VERSION 5.7 ;
  NOWIREEXTENSIONATPIN ON ;
  DIVIDERCHAR "/" ;
  BUSBITCHARS "[]" ;
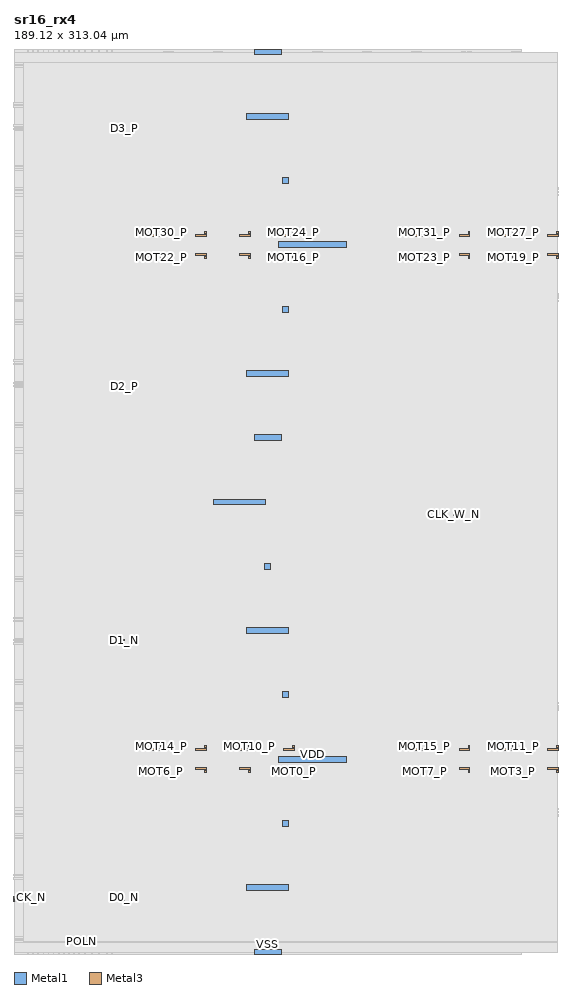
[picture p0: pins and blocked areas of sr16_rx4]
MACRO sr16_rx4
  CLASS BLOCK ;
  FOREIGN sr16_rx4 ;
  ORIGIN 0.000 0.000 ;
  SIZE 189.120 BY 313.040 ;
  PIN VSS
    DIRECTION INOUT ;
    USE GROUND ;
    USE GROUND ;
    PORT
      LAYER Metal1 ;
        RECT 83.570 -1.000 92.870 1.000 ;
    END
    PORT
      LAYER Metal1 ;
        RECT 93.560 43.720 95.560 45.720 ;
    END
    PORT
      LAYER Metal1 ;
        RECT 93.560 88.440 95.560 90.440 ;
    END
    PORT
      LAYER Metal1 ;
        RECT 87.280 133.160 89.280 135.160 ;
    END
    PORT
      LAYER Metal1 ;
        RECT 83.570 177.880 92.870 179.880 ;
    END
    PORT
      LAYER Metal1 ;
        RECT 93.560 222.600 95.560 224.600 ;
    END
    PORT
      LAYER Metal1 ;
        RECT 93.560 267.320 95.560 269.320 ;
    END
    PORT
      LAYER Metal1 ;
        RECT 83.570 312.040 92.870 314.040 ;
    END
  END VSS
  PIN VDD
    DIRECTION INOUT ;
    USE POWER ;
    USE POWER ;
    PORT
      LAYER Metal1 ;
        RECT 80.820 21.360 95.400 23.360 ;
    END
    PORT
      LAYER Metal1 ;
        RECT 91.940 66.080 115.740 68.080 ;
    END
    PORT
      LAYER Metal1 ;
        RECT 80.820 110.800 95.400 112.800 ;
    END
    PORT
      LAYER Metal1 ;
        RECT 69.450 155.520 87.440 157.520 ;
    END
    PORT
      LAYER Metal1 ;
        RECT 80.820 200.240 95.400 202.240 ;
    END
    PORT
      LAYER Metal1 ;
        RECT 91.940 244.960 115.740 246.960 ;
    END
    PORT
      LAYER Metal1 ;
        RECT 80.820 289.680 95.400 291.680 ;
    END
  END VDD
  PIN CK_N
    DIRECTION INPUT ;
    USE SIGNAL ;
    ANTENNAGATEAREA 6.480000 ;
    PORT
      LAYER Metal3 ;
        RECT -0.150 18.760 0.150 19.360 ;
    END
  END CK_N
  PIN CK_P
    DIRECTION INPUT ;
    USE SIGNAL ;
    ANTENNAGATEAREA 6.480000 ;
    PORT
      LAYER Metal3 ;
        RECT -0.150 17.660 0.150 18.260 ;
    END
  END CK_P
  PIN D0_N
    DIRECTION INPUT ;
    USE SIGNAL ;
    ANTENNAGATEAREA 1.778400 ;
    PORT
      LAYER Metal3 ;
        RECT 38.170 18.760 38.470 19.360 ;
    END
  END D0_N
  PIN D0_P
    DIRECTION INPUT ;
    USE SIGNAL ;
    ANTENNAGATEAREA 1.778400 ;
    PORT
      LAYER Metal3 ;
        RECT 38.170 17.660 38.470 18.260 ;
    END
  END D0_P
  PIN D1_N
    DIRECTION INPUT ;
    USE SIGNAL ;
    ANTENNAGATEAREA 1.778400 ;
    PORT
      LAYER Metal3 ;
        RECT 38.170 108.200 38.470 108.800 ;
    END
  END D1_N
  PIN D1_P
    DIRECTION INPUT ;
    USE SIGNAL ;
    ANTENNAGATEAREA 1.778400 ;
    PORT
      LAYER Metal3 ;
        RECT 38.170 107.100 38.470 107.700 ;
    END
  END D1_P
  PIN D2_N
    DIRECTION INPUT ;
    USE SIGNAL ;
    ANTENNAGATEAREA 1.778400 ;
    PORT
      LAYER Metal3 ;
        RECT 38.170 197.640 38.470 198.240 ;
    END
  END D2_N
  PIN D2_P
    DIRECTION INPUT ;
    USE SIGNAL ;
    ANTENNAGATEAREA 1.778400 ;
    PORT
      LAYER Metal3 ;
        RECT 38.170 196.540 38.470 197.140 ;
    END
  END D2_P
  PIN D3_N
    DIRECTION INPUT ;
    USE SIGNAL ;
    ANTENNAGATEAREA 1.778400 ;
    PORT
      LAYER Metal3 ;
        RECT 38.170 287.080 38.470 287.680 ;
    END
  END D3_N
  PIN D3_P
    DIRECTION INPUT ;
    USE SIGNAL ;
    ANTENNAGATEAREA 1.778400 ;
    PORT
      LAYER Metal3 ;
        RECT 38.170 285.980 38.470 286.580 ;
    END
  END D3_P
  PIN POLN
    DIRECTION INPUT ;
    USE SIGNAL ;
    ANTENNAGATEAREA 474.759979 ;
    PORT
      LAYER Metal3 ;
        RECT 23.370 3.580 23.670 3.880 ;
    END
  END POLN
  PIN MOT0_N
    DIRECTION OUTPUT ;
    USE SIGNAL ;
    ANTENNAGATEAREA 0.693600 ;
    ANTENNADIFFAREA 1.979400 ;
    PORT
      LAYER Metal3 ;
        RECT 93.845 63.480 97.590 64.080 ;
    END
  END MOT0_N
  PIN MOT0_P
    DIRECTION OUTPUT ;
    USE SIGNAL ;
    ANTENNAGATEAREA 0.693600 ;
    ANTENNADIFFAREA 1.979400 ;
    PORT
      LAYER Metal3 ;
        RECT 97.015 62.380 97.590 62.980 ;
    END
  END MOT0_P
  PIN MOT1_N
    DIRECTION OUTPUT ;
    USE SIGNAL ;
    ANTENNAGATEAREA 0.693600 ;
    ANTENNADIFFAREA 1.979400 ;
    PORT
      LAYER Metal3 ;
        RECT 185.525 63.480 189.270 64.080 ;
    END
  END MOT1_N
  PIN MOT1_P
    DIRECTION OUTPUT ;
    USE SIGNAL ;
    ANTENNAGATEAREA 0.693600 ;
    ANTENNADIFFAREA 1.979400 ;
    PORT
      LAYER Metal3 ;
        RECT 188.695 62.380 189.270 62.980 ;
    END
  END MOT1_P
  PIN MOT2_N
    DIRECTION OUTPUT ;
    USE SIGNAL ;
    ANTENNAGATEAREA 0.693600 ;
    ANTENNADIFFAREA 1.979400 ;
    PORT
      LAYER Metal3 ;
        RECT 78.485 63.480 82.230 64.080 ;
    END
  END MOT2_N
  PIN MOT2_P
    DIRECTION OUTPUT ;
    USE SIGNAL ;
    ANTENNAGATEAREA 0.693600 ;
    ANTENNADIFFAREA 1.979400 ;
    PORT
      LAYER Metal3 ;
        RECT 81.655 62.380 82.230 62.980 ;
    END
  END MOT2_P
  PIN MOT3_N
    DIRECTION OUTPUT ;
    USE SIGNAL ;
    ANTENNAGATEAREA 0.693600 ;
    ANTENNADIFFAREA 1.979400 ;
    PORT
      LAYER Metal3 ;
        RECT 170.165 63.480 173.910 64.080 ;
    END
  END MOT3_N
  PIN MOT3_P
    DIRECTION OUTPUT ;
    USE SIGNAL ;
    ANTENNAGATEAREA 0.693600 ;
    ANTENNADIFFAREA 1.979400 ;
    PORT
      LAYER Metal3 ;
        RECT 173.335 62.380 173.910 62.980 ;
    END
  END MOT3_P
  PIN MOT4_N
    DIRECTION OUTPUT ;
    USE SIGNAL ;
    ANTENNAGATEAREA 0.693600 ;
    ANTENNADIFFAREA 1.979400 ;
    PORT
      LAYER Metal3 ;
        RECT 63.125 63.480 66.870 64.080 ;
    END
  END MOT4_N
  PIN MOT4_P
    DIRECTION OUTPUT ;
    USE SIGNAL ;
    ANTENNAGATEAREA 0.693600 ;
    ANTENNADIFFAREA 1.979400 ;
    PORT
      LAYER Metal3 ;
        RECT 66.295 62.380 66.870 62.980 ;
    END
  END MOT4_P
  PIN MOT5_N
    DIRECTION OUTPUT ;
    USE SIGNAL ;
    ANTENNAGATEAREA 0.693600 ;
    ANTENNADIFFAREA 1.979400 ;
    PORT
      LAYER Metal3 ;
        RECT 154.805 63.480 158.550 64.080 ;
    END
  END MOT5_N
  PIN MOT5_P
    DIRECTION OUTPUT ;
    USE SIGNAL ;
    ANTENNAGATEAREA 0.693600 ;
    ANTENNADIFFAREA 1.979400 ;
    PORT
      LAYER Metal3 ;
        RECT 157.975 62.380 158.550 62.980 ;
    END
  END MOT5_P
  PIN MOT6_N
    DIRECTION OUTPUT ;
    USE SIGNAL ;
    ANTENNAGATEAREA 0.693600 ;
    ANTENNADIFFAREA 1.979400 ;
    PORT
      LAYER Metal3 ;
        RECT 47.765 63.480 51.510 64.080 ;
    END
  END MOT6_N
  PIN MOT6_P
    DIRECTION OUTPUT ;
    USE SIGNAL ;
    ANTENNAGATEAREA 0.693600 ;
    ANTENNADIFFAREA 1.979400 ;
    PORT
      LAYER Metal3 ;
        RECT 50.935 62.380 51.510 62.980 ;
    END
  END MOT6_P
  PIN MOT7_N
    DIRECTION OUTPUT ;
    USE SIGNAL ;
    ANTENNAGATEAREA 0.693600 ;
    ANTENNADIFFAREA 1.979400 ;
    PORT
      LAYER Metal3 ;
        RECT 139.445 63.480 143.190 64.080 ;
    END
  END MOT7_N
  PIN MOT7_P
    DIRECTION OUTPUT ;
    USE SIGNAL ;
    ANTENNAGATEAREA 0.693600 ;
    ANTENNADIFFAREA 1.979400 ;
    PORT
      LAYER Metal3 ;
        RECT 142.615 62.380 143.190 62.980 ;
    END
  END MOT7_P
  PIN MOT8_N
    DIRECTION OUTPUT ;
    USE SIGNAL ;
    ANTENNAGATEAREA 0.693600 ;
    ANTENNADIFFAREA 1.979400 ;
    PORT
      LAYER Metal3 ;
        RECT 93.845 70.080 97.590 70.680 ;
    END
  END MOT8_N
  PIN MOT8_P
    DIRECTION OUTPUT ;
    USE SIGNAL ;
    ANTENNAGATEAREA 0.693600 ;
    ANTENNADIFFAREA 1.979400 ;
    PORT
      LAYER Metal3 ;
        RECT 97.015 71.180 97.590 71.780 ;
    END
  END MOT8_P
  PIN MOT9_N
    DIRECTION OUTPUT ;
    USE SIGNAL ;
    ANTENNAGATEAREA 0.693600 ;
    ANTENNADIFFAREA 1.979400 ;
    PORT
      LAYER Metal3 ;
        RECT 185.525 70.080 189.270 70.680 ;
    END
  END MOT9_N
  PIN MOT9_P
    DIRECTION OUTPUT ;
    USE SIGNAL ;
    ANTENNAGATEAREA 0.693600 ;
    ANTENNADIFFAREA 1.979400 ;
    PORT
      LAYER Metal3 ;
        RECT 188.695 71.180 189.270 71.780 ;
    END
  END MOT9_P
  PIN MOT10_N
    DIRECTION OUTPUT ;
    USE SIGNAL ;
    ANTENNAGATEAREA 0.693600 ;
    ANTENNADIFFAREA 1.979400 ;
    PORT
      LAYER Metal3 ;
        RECT 78.485 70.080 82.230 70.680 ;
    END
  END MOT10_N
  PIN MOT10_P
    DIRECTION OUTPUT ;
    USE SIGNAL ;
    ANTENNAGATEAREA 0.693600 ;
    ANTENNADIFFAREA 1.979400 ;
    PORT
      LAYER Metal3 ;
        RECT 81.655 71.180 82.230 71.780 ;
    END
  END MOT10_P
  PIN MOT11_N
    DIRECTION OUTPUT ;
    USE SIGNAL ;
    ANTENNAGATEAREA 0.693600 ;
    ANTENNADIFFAREA 1.979400 ;
    PORT
      LAYER Metal3 ;
        RECT 170.165 70.080 173.910 70.680 ;
    END
  END MOT11_N
  PIN MOT11_P
    DIRECTION OUTPUT ;
    USE SIGNAL ;
    ANTENNAGATEAREA 0.693600 ;
    ANTENNADIFFAREA 1.979400 ;
    PORT
      LAYER Metal3 ;
        RECT 173.335 71.180 173.910 71.780 ;
    END
  END MOT11_P
  PIN MOT12_N
    DIRECTION OUTPUT ;
    USE SIGNAL ;
    ANTENNAGATEAREA 0.693600 ;
    ANTENNADIFFAREA 1.979400 ;
    PORT
      LAYER Metal3 ;
        RECT 63.125 70.080 66.870 70.680 ;
    END
  END MOT12_N
  PIN MOT12_P
    DIRECTION OUTPUT ;
    USE SIGNAL ;
    ANTENNAGATEAREA 0.693600 ;
    ANTENNADIFFAREA 1.979400 ;
    PORT
      LAYER Metal3 ;
        RECT 66.295 71.180 66.870 71.780 ;
    END
  END MOT12_P
  PIN MOT13_N
    DIRECTION OUTPUT ;
    USE SIGNAL ;
    ANTENNAGATEAREA 0.693600 ;
    ANTENNADIFFAREA 1.979400 ;
    PORT
      LAYER Metal3 ;
        RECT 154.805 70.080 158.550 70.680 ;
    END
  END MOT13_N
  PIN MOT13_P
    DIRECTION OUTPUT ;
    USE SIGNAL ;
    ANTENNAGATEAREA 0.693600 ;
    ANTENNADIFFAREA 1.979400 ;
    PORT
      LAYER Metal3 ;
        RECT 157.975 71.180 158.550 71.780 ;
    END
  END MOT13_P
  PIN MOT14_N
    DIRECTION OUTPUT ;
    USE SIGNAL ;
    ANTENNAGATEAREA 0.693600 ;
    ANTENNADIFFAREA 1.979400 ;
    PORT
      LAYER Metal3 ;
        RECT 47.765 70.080 51.510 70.680 ;
    END
  END MOT14_N
  PIN MOT14_P
    DIRECTION OUTPUT ;
    USE SIGNAL ;
    ANTENNAGATEAREA 0.693600 ;
    ANTENNADIFFAREA 1.979400 ;
    PORT
      LAYER Metal3 ;
        RECT 50.935 71.180 51.510 71.780 ;
    END
  END MOT14_P
  PIN MOT15_N
    DIRECTION OUTPUT ;
    USE SIGNAL ;
    ANTENNAGATEAREA 0.693600 ;
    ANTENNADIFFAREA 1.979400 ;
    PORT
      LAYER Metal3 ;
        RECT 139.445 70.080 143.190 70.680 ;
    END
  END MOT15_N
  PIN MOT15_P
    DIRECTION OUTPUT ;
    USE SIGNAL ;
    ANTENNAGATEAREA 0.693600 ;
    ANTENNADIFFAREA 1.979400 ;
    PORT
      LAYER Metal3 ;
        RECT 142.615 71.180 143.190 71.780 ;
    END
  END MOT15_P
  PIN MOT16_N
    DIRECTION OUTPUT ;
    USE SIGNAL ;
    ANTENNAGATEAREA 0.693600 ;
    ANTENNADIFFAREA 1.979400 ;
    PORT
      LAYER Metal3 ;
        RECT 93.845 242.360 97.590 242.960 ;
    END
  END MOT16_N
  PIN MOT16_P
    DIRECTION OUTPUT ;
    USE SIGNAL ;
    ANTENNAGATEAREA 0.693600 ;
    ANTENNADIFFAREA 1.979400 ;
    PORT
      LAYER Metal3 ;
        RECT 97.015 241.260 97.590 241.860 ;
    END
  END MOT16_P
  PIN MOT17_N
    DIRECTION OUTPUT ;
    USE SIGNAL ;
    ANTENNAGATEAREA 0.693600 ;
    ANTENNADIFFAREA 1.979400 ;
    PORT
      LAYER Metal3 ;
        RECT 185.525 242.360 189.270 242.960 ;
    END
  END MOT17_N
  PIN MOT17_P
    DIRECTION OUTPUT ;
    USE SIGNAL ;
    ANTENNAGATEAREA 0.693600 ;
    ANTENNADIFFAREA 1.979400 ;
    PORT
      LAYER Metal3 ;
        RECT 188.695 241.260 189.270 241.860 ;
    END
  END MOT17_P
  PIN MOT18_N
    DIRECTION OUTPUT ;
    USE SIGNAL ;
    ANTENNAGATEAREA 0.693600 ;
    ANTENNADIFFAREA 1.979400 ;
    PORT
      LAYER Metal3 ;
        RECT 78.485 242.360 82.230 242.960 ;
    END
  END MOT18_N
  PIN MOT18_P
    DIRECTION OUTPUT ;
    USE SIGNAL ;
    ANTENNAGATEAREA 0.693600 ;
    ANTENNADIFFAREA 1.979400 ;
    PORT
      LAYER Metal3 ;
        RECT 81.655 241.260 82.230 241.860 ;
    END
  END MOT18_P
  PIN MOT19_N
    DIRECTION OUTPUT ;
    USE SIGNAL ;
    ANTENNAGATEAREA 0.693600 ;
    ANTENNADIFFAREA 1.979400 ;
    PORT
      LAYER Metal3 ;
        RECT 170.165 242.360 173.910 242.960 ;
    END
  END MOT19_N
  PIN MOT19_P
    DIRECTION OUTPUT ;
    USE SIGNAL ;
    ANTENNAGATEAREA 0.693600 ;
    ANTENNADIFFAREA 1.979400 ;
    PORT
      LAYER Metal3 ;
        RECT 173.335 241.260 173.910 241.860 ;
    END
  END MOT19_P
  PIN MOT20_N
    DIRECTION OUTPUT ;
    USE SIGNAL ;
    ANTENNAGATEAREA 0.693600 ;
    ANTENNADIFFAREA 1.979400 ;
    PORT
      LAYER Metal3 ;
        RECT 63.125 242.360 66.870 242.960 ;
    END
  END MOT20_N
  PIN MOT20_P
    DIRECTION OUTPUT ;
    USE SIGNAL ;
    ANTENNAGATEAREA 0.693600 ;
    ANTENNADIFFAREA 1.979400 ;
    PORT
      LAYER Metal3 ;
        RECT 66.295 241.260 66.870 241.860 ;
    END
  END MOT20_P
  PIN MOT21_N
    DIRECTION OUTPUT ;
    USE SIGNAL ;
    ANTENNAGATEAREA 0.693600 ;
    ANTENNADIFFAREA 1.979400 ;
    PORT
      LAYER Metal3 ;
        RECT 154.805 242.360 158.550 242.960 ;
    END
  END MOT21_N
  PIN MOT21_P
    DIRECTION OUTPUT ;
    USE SIGNAL ;
    ANTENNAGATEAREA 0.693600 ;
    ANTENNADIFFAREA 1.979400 ;
    PORT
      LAYER Metal3 ;
        RECT 157.975 241.260 158.550 241.860 ;
    END
  END MOT21_P
  PIN MOT22_N
    DIRECTION OUTPUT ;
    USE SIGNAL ;
    ANTENNAGATEAREA 0.693600 ;
    ANTENNADIFFAREA 1.979400 ;
    PORT
      LAYER Metal3 ;
        RECT 47.765 242.360 51.510 242.960 ;
    END
  END MOT22_N
  PIN MOT22_P
    DIRECTION OUTPUT ;
    USE SIGNAL ;
    ANTENNAGATEAREA 0.693600 ;
    ANTENNADIFFAREA 1.979400 ;
    PORT
      LAYER Metal3 ;
        RECT 50.935 241.260 51.510 241.860 ;
    END
  END MOT22_P
  PIN MOT23_N
    DIRECTION OUTPUT ;
    USE SIGNAL ;
    ANTENNAGATEAREA 0.693600 ;
    ANTENNADIFFAREA 1.979400 ;
    PORT
      LAYER Metal3 ;
        RECT 139.445 242.360 143.190 242.960 ;
    END
  END MOT23_N
  PIN MOT23_P
    DIRECTION OUTPUT ;
    USE SIGNAL ;
    ANTENNAGATEAREA 0.693600 ;
    ANTENNADIFFAREA 1.979400 ;
    PORT
      LAYER Metal3 ;
        RECT 142.615 241.260 143.190 241.860 ;
    END
  END MOT23_P
  PIN MOT24_N
    DIRECTION OUTPUT ;
    USE SIGNAL ;
    ANTENNAGATEAREA 0.693600 ;
    ANTENNADIFFAREA 1.979400 ;
    PORT
      LAYER Metal3 ;
        RECT 93.845 248.960 97.590 249.560 ;
    END
  END MOT24_N
  PIN MOT24_P
    DIRECTION OUTPUT ;
    USE SIGNAL ;
    ANTENNAGATEAREA 0.693600 ;
    ANTENNADIFFAREA 1.979400 ;
    PORT
      LAYER Metal3 ;
        RECT 97.015 250.060 97.590 250.660 ;
    END
  END MOT24_P
  PIN MOT25_N
    DIRECTION OUTPUT ;
    USE SIGNAL ;
    ANTENNAGATEAREA 0.693600 ;
    ANTENNADIFFAREA 1.979400 ;
    PORT
      LAYER Metal3 ;
        RECT 185.525 248.960 189.270 249.560 ;
    END
  END MOT25_N
  PIN MOT25_P
    DIRECTION OUTPUT ;
    USE SIGNAL ;
    ANTENNAGATEAREA 0.693600 ;
    ANTENNADIFFAREA 1.979400 ;
    PORT
      LAYER Metal3 ;
        RECT 188.695 250.060 189.270 250.660 ;
    END
  END MOT25_P
  PIN MOT26_N
    DIRECTION OUTPUT ;
    USE SIGNAL ;
    ANTENNAGATEAREA 0.693600 ;
    ANTENNADIFFAREA 1.979400 ;
    PORT
      LAYER Metal3 ;
        RECT 78.485 248.960 82.230 249.560 ;
    END
  END MOT26_N
  PIN MOT26_P
    DIRECTION OUTPUT ;
    USE SIGNAL ;
    ANTENNAGATEAREA 0.693600 ;
    ANTENNADIFFAREA 1.979400 ;
    PORT
      LAYER Metal3 ;
        RECT 81.655 250.060 82.230 250.660 ;
    END
  END MOT26_P
  PIN MOT27_N
    DIRECTION OUTPUT ;
    USE SIGNAL ;
    ANTENNAGATEAREA 0.693600 ;
    ANTENNADIFFAREA 1.979400 ;
    PORT
      LAYER Metal3 ;
        RECT 170.165 248.960 173.910 249.560 ;
    END
  END MOT27_N
  PIN MOT27_P
    DIRECTION OUTPUT ;
    USE SIGNAL ;
    ANTENNAGATEAREA 0.693600 ;
    ANTENNADIFFAREA 1.979400 ;
    PORT
      LAYER Metal3 ;
        RECT 173.335 250.060 173.910 250.660 ;
    END
  END MOT27_P
  PIN MOT28_N
    DIRECTION OUTPUT ;
    USE SIGNAL ;
    ANTENNAGATEAREA 0.693600 ;
    ANTENNADIFFAREA 1.979400 ;
    PORT
      LAYER Metal3 ;
        RECT 63.125 248.960 66.870 249.560 ;
    END
  END MOT28_N
  PIN MOT28_P
    DIRECTION OUTPUT ;
    USE SIGNAL ;
    ANTENNAGATEAREA 0.693600 ;
    ANTENNADIFFAREA 1.979400 ;
    PORT
      LAYER Metal3 ;
        RECT 66.295 250.060 66.870 250.660 ;
    END
  END MOT28_P
  PIN MOT29_N
    DIRECTION OUTPUT ;
    USE SIGNAL ;
    ANTENNAGATEAREA 0.693600 ;
    ANTENNADIFFAREA 1.979400 ;
    PORT
      LAYER Metal3 ;
        RECT 154.805 248.960 158.550 249.560 ;
    END
  END MOT29_N
  PIN MOT29_P
    DIRECTION OUTPUT ;
    USE SIGNAL ;
    ANTENNAGATEAREA 0.693600 ;
    ANTENNADIFFAREA 1.979400 ;
    PORT
      LAYER Metal3 ;
        RECT 157.975 250.060 158.550 250.660 ;
    END
  END MOT29_P
  PIN MOT30_N
    DIRECTION OUTPUT ;
    USE SIGNAL ;
    ANTENNAGATEAREA 0.693600 ;
    ANTENNADIFFAREA 1.979400 ;
    PORT
      LAYER Metal3 ;
        RECT 47.765 248.960 51.510 249.560 ;
    END
  END MOT30_N
  PIN MOT30_P
    DIRECTION OUTPUT ;
    USE SIGNAL ;
    ANTENNAGATEAREA 0.693600 ;
    ANTENNADIFFAREA 1.979400 ;
    PORT
      LAYER Metal3 ;
        RECT 50.935 250.060 51.510 250.660 ;
    END
  END MOT30_P
  PIN MOT31_N
    DIRECTION OUTPUT ;
    USE SIGNAL ;
    ANTENNAGATEAREA 0.693600 ;
    ANTENNADIFFAREA 1.979400 ;
    PORT
      LAYER Metal3 ;
        RECT 139.445 248.960 143.190 249.560 ;
    END
  END MOT31_N
  PIN MOT31_P
    DIRECTION OUTPUT ;
    USE SIGNAL ;
    ANTENNAGATEAREA 0.693600 ;
    ANTENNADIFFAREA 1.979400 ;
    PORT
      LAYER Metal3 ;
        RECT 142.615 250.060 143.190 250.660 ;
    END
  END MOT31_P
  PIN CLK_W_N
    DIRECTION OUTPUT ;
    USE SIGNAL ;
    ANTENNAGATEAREA 1.906200 ;
    ANTENNADIFFAREA 1.979400 ;
    PORT
      LAYER Metal3 ;
        RECT 152.890 151.970 153.190 152.270 ;
    END
  END CLK_W_N
  PIN CLK_W_P
    DIRECTION OUTPUT ;
    USE SIGNAL ;
    ANTENNAGATEAREA 1.906200 ;
    ANTENNADIFFAREA 1.979400 ;
    PORT
      LAYER Metal3 ;
        RECT 152.890 153.070 153.190 153.370 ;
    END
  END CLK_W_P
  OBS
      LAYER GatPoly ;
        RECT 4.810 0.540 188.100 312.500 ;
      LAYER Metal1 ;
        RECT 0.000 312.905 83.570 314.040 ;
        RECT 92.870 313.040 176.560 314.040 ;
        RECT 0.000 311.860 83.390 312.905 ;
        RECT 92.870 312.360 189.120 313.040 ;
        RECT 93.050 311.860 189.120 312.360 ;
        RECT 0.000 291.860 189.120 311.860 ;
        RECT 0.000 289.500 80.640 291.860 ;
        RECT 95.580 289.500 189.120 291.860 ;
        RECT 0.000 269.500 189.120 289.500 ;
        RECT 0.000 267.140 93.380 269.500 ;
        RECT 95.740 267.140 189.120 269.500 ;
        RECT 0.000 247.140 189.120 267.140 ;
        RECT 0.000 244.780 91.760 247.140 ;
        RECT 115.920 244.780 189.120 247.140 ;
        RECT 0.000 224.780 189.120 244.780 ;
        RECT 0.000 222.420 93.380 224.780 ;
        RECT 95.740 222.420 189.120 224.780 ;
        RECT 0.000 202.420 189.120 222.420 ;
        RECT 0.000 200.060 80.640 202.420 ;
        RECT 95.580 200.060 189.120 202.420 ;
        RECT 0.000 180.060 189.120 200.060 ;
        RECT 0.000 177.700 83.390 180.060 ;
        RECT 93.050 177.700 189.120 180.060 ;
        RECT 0.000 157.700 189.120 177.700 ;
        RECT 0.000 155.340 69.270 157.700 ;
        RECT 87.620 155.340 189.120 157.700 ;
        RECT 0.000 135.340 189.120 155.340 ;
        RECT 0.000 132.980 87.100 135.340 ;
        RECT 89.460 132.980 189.120 135.340 ;
        RECT 0.000 112.980 189.120 132.980 ;
        RECT 0.000 110.620 80.640 112.980 ;
        RECT 95.580 110.620 189.120 112.980 ;
        RECT 0.000 90.620 189.120 110.620 ;
        RECT 0.000 88.260 93.380 90.620 ;
        RECT 95.740 88.260 189.120 90.620 ;
        RECT 0.000 68.260 189.120 88.260 ;
        RECT 0.000 65.900 91.760 68.260 ;
        RECT 115.920 65.900 189.120 68.260 ;
        RECT 0.000 45.900 189.120 65.900 ;
        RECT 0.000 43.540 93.380 45.900 ;
        RECT 95.740 43.540 189.120 45.900 ;
        RECT 0.000 23.540 189.120 43.540 ;
        RECT 0.000 21.180 80.640 23.540 ;
        RECT 95.580 21.180 189.120 23.540 ;
        RECT 0.000 1.180 189.120 21.180 ;
        RECT 0.000 0.135 83.390 1.180 ;
        RECT 93.050 0.680 189.120 1.180 ;
        RECT 0.000 -1.000 83.570 0.135 ;
        RECT 92.870 0.000 189.120 0.680 ;
        RECT 92.870 -1.000 176.560 0.000 ;
      LAYER Metal2 ;
        RECT 4.815 313.040 5.100 313.660 ;
        RECT 6.575 313.040 6.860 313.660 ;
        RECT 8.335 313.040 8.620 313.660 ;
        RECT 10.095 313.040 10.380 313.660 ;
        RECT 11.855 313.040 12.140 313.660 ;
        RECT 13.615 313.040 13.900 313.660 ;
        RECT 15.375 313.040 15.660 313.660 ;
        RECT 17.135 313.040 17.420 313.660 ;
        RECT 18.895 313.040 19.180 313.660 ;
        RECT 20.655 313.040 20.940 313.660 ;
        RECT 22.415 313.040 22.700 313.660 ;
        RECT 24.450 313.040 24.770 313.660 ;
        RECT 26.940 313.040 27.260 313.660 ;
        RECT 29.440 313.040 29.760 313.660 ;
        RECT 32.100 313.040 32.420 313.660 ;
        RECT 33.770 313.040 34.090 313.660 ;
        RECT 0.510 0.000 188.795 313.040 ;
        RECT 4.815 -0.620 5.100 0.000 ;
        RECT 6.575 -0.620 6.860 0.000 ;
        RECT 8.335 -0.620 8.620 0.000 ;
        RECT 10.095 -0.620 10.380 0.000 ;
        RECT 11.855 -0.620 12.140 0.000 ;
        RECT 13.615 -0.620 13.900 0.000 ;
        RECT 15.375 -0.620 15.660 0.000 ;
        RECT 17.135 -0.620 17.420 0.000 ;
        RECT 18.895 -0.620 19.180 0.000 ;
        RECT 20.655 -0.620 20.940 0.000 ;
        RECT 22.415 -0.620 22.700 0.000 ;
        RECT 24.450 -0.620 24.770 0.000 ;
        RECT 26.940 -0.620 27.260 0.000 ;
        RECT 29.440 -0.620 29.760 0.000 ;
        RECT 32.100 -0.620 32.420 0.000 ;
        RECT 33.770 -0.620 34.090 0.000 ;
      LAYER Metal3 ;
        RECT 51.970 313.040 52.570 313.190 ;
        RECT 52.870 313.040 53.470 313.190 ;
        RECT 53.890 313.040 54.490 313.190 ;
        RECT 54.790 313.040 55.390 313.190 ;
        RECT 69.250 313.040 69.850 313.190 ;
        RECT 70.150 313.040 70.750 313.190 ;
        RECT 71.170 313.040 71.770 313.190 ;
        RECT 72.070 313.040 72.670 313.190 ;
        RECT 86.530 313.040 87.130 313.190 ;
        RECT 87.430 313.040 88.030 313.190 ;
        RECT 88.450 313.040 89.050 313.190 ;
        RECT 89.350 313.040 89.950 313.190 ;
        RECT 103.810 313.040 104.410 313.190 ;
        RECT 104.710 313.040 105.310 313.190 ;
        RECT 105.730 313.040 106.330 313.190 ;
        RECT 106.630 313.040 107.230 313.190 ;
        RECT 121.090 313.040 121.690 313.190 ;
        RECT 121.990 313.040 122.590 313.190 ;
        RECT 123.010 313.040 123.610 313.190 ;
        RECT 123.910 313.040 124.510 313.190 ;
        RECT 138.370 313.040 138.970 313.190 ;
        RECT 139.270 313.040 139.870 313.190 ;
        RECT 140.290 313.040 140.890 313.190 ;
        RECT 141.190 313.040 141.790 313.190 ;
        RECT 155.650 313.040 156.250 313.190 ;
        RECT 156.550 313.040 157.150 313.190 ;
        RECT 157.570 313.040 158.170 313.190 ;
        RECT 158.470 313.040 159.070 313.190 ;
        RECT 172.930 313.040 173.530 313.190 ;
        RECT 173.830 313.040 174.430 313.190 ;
        RECT 174.850 313.040 175.450 313.190 ;
        RECT 175.750 313.040 176.350 313.190 ;
        RECT 0.000 309.390 189.120 313.040 ;
        RECT 0.000 308.770 36.090 309.390 ;
        RECT 36.710 308.770 189.120 309.390 ;
        RECT 0.000 308.290 189.120 308.770 ;
        RECT 0.000 307.670 36.090 308.290 ;
        RECT 36.710 307.670 189.120 308.290 ;
        RECT 0.000 295.390 189.120 307.670 ;
        RECT 0.000 295.380 68.730 295.390 ;
        RECT -0.150 294.780 68.730 295.380 ;
        RECT 0.000 294.770 68.730 294.780 ;
        RECT 69.350 294.770 172.410 295.390 ;
        RECT 173.030 294.770 189.120 295.390 ;
        RECT 0.000 294.290 189.120 294.770 ;
        RECT 0.000 294.280 68.730 294.290 ;
        RECT -0.150 293.680 68.730 294.280 ;
        RECT 0.000 293.670 68.730 293.680 ;
        RECT 69.350 293.670 172.410 294.290 ;
        RECT 173.030 293.670 189.120 294.290 ;
        RECT 0.000 287.890 189.120 293.670 ;
        RECT 0.000 287.680 37.960 287.890 ;
        RECT -0.150 287.080 37.960 287.680 ;
        RECT 0.000 286.870 37.960 287.080 ;
        RECT 38.680 287.690 189.120 287.890 ;
        RECT 38.680 287.070 68.730 287.690 ;
        RECT 69.350 287.070 172.410 287.690 ;
        RECT 173.030 287.070 189.120 287.690 ;
        RECT 38.680 286.870 189.120 287.070 ;
        RECT 0.000 286.790 189.120 286.870 ;
        RECT 0.000 286.580 37.960 286.790 ;
        RECT -0.150 285.980 37.960 286.580 ;
        RECT 0.000 285.770 37.960 285.980 ;
        RECT 38.680 286.590 189.120 286.790 ;
        RECT 38.680 285.970 68.730 286.590 ;
        RECT 69.350 285.970 172.410 286.590 ;
        RECT 173.030 285.970 189.120 286.590 ;
        RECT 38.680 285.770 189.120 285.970 ;
        RECT 0.000 273.690 189.120 285.770 ;
        RECT 0.000 273.070 36.090 273.690 ;
        RECT 36.710 273.070 189.120 273.690 ;
        RECT 0.000 272.590 189.120 273.070 ;
        RECT 0.000 271.970 36.090 272.590 ;
        RECT 36.710 271.970 189.120 272.590 ;
        RECT 0.000 265.760 189.120 271.970 ;
        RECT 0.000 265.160 189.270 265.760 ;
        RECT 0.000 264.870 189.120 265.160 ;
        RECT 0.000 263.850 37.560 264.870 ;
        RECT 38.280 263.850 129.240 264.870 ;
        RECT 129.960 264.660 189.120 264.870 ;
        RECT 129.960 264.060 189.270 264.660 ;
        RECT 129.960 263.850 189.120 264.060 ;
        RECT 0.000 263.770 189.120 263.850 ;
        RECT 0.000 262.750 37.560 263.770 ;
        RECT 38.280 262.750 129.240 263.770 ;
        RECT 129.960 263.560 189.120 263.770 ;
        RECT 129.960 262.960 189.270 263.560 ;
        RECT 129.960 262.750 189.120 262.960 ;
        RECT 0.000 250.870 189.120 262.750 ;
        RECT 0.000 250.000 22.255 250.870 ;
        RECT 30.120 250.000 50.725 250.870 ;
        RECT 0.000 249.850 50.725 250.000 ;
        RECT 51.720 249.850 66.085 250.870 ;
        RECT 67.080 249.850 81.445 250.870 ;
        RECT 82.440 249.850 96.805 250.870 ;
        RECT 97.800 250.000 113.935 250.870 ;
        RECT 121.800 250.000 142.405 250.870 ;
        RECT 97.800 249.850 142.405 250.000 ;
        RECT 143.400 249.850 157.765 250.870 ;
        RECT 158.760 249.850 173.125 250.870 ;
        RECT 174.120 249.850 188.485 250.870 ;
        RECT 0.000 249.770 189.120 249.850 ;
        RECT 0.000 248.750 27.755 249.770 ;
        RECT 30.120 248.750 47.555 249.770 ;
        RECT 51.720 248.750 62.915 249.770 ;
        RECT 67.080 248.750 78.275 249.770 ;
        RECT 82.440 248.750 93.635 249.770 ;
        RECT 97.800 248.750 119.435 249.770 ;
        RECT 121.800 248.750 139.235 249.770 ;
        RECT 143.400 248.750 154.595 249.770 ;
        RECT 158.760 248.750 169.955 249.770 ;
        RECT 174.120 248.750 185.315 249.770 ;
        RECT 0.000 243.170 189.120 248.750 ;
        RECT 0.000 242.150 27.755 243.170 ;
        RECT 30.120 242.150 47.555 243.170 ;
        RECT 51.720 242.150 62.915 243.170 ;
        RECT 67.080 242.150 78.275 243.170 ;
        RECT 82.440 242.150 93.635 243.170 ;
        RECT 97.800 242.150 119.435 243.170 ;
        RECT 121.800 242.150 139.235 243.170 ;
        RECT 143.400 242.150 154.595 243.170 ;
        RECT 158.760 242.150 169.955 243.170 ;
        RECT 174.120 242.150 185.315 243.170 ;
        RECT 0.000 242.070 189.120 242.150 ;
        RECT 0.000 241.920 50.725 242.070 ;
        RECT 0.000 241.050 22.255 241.920 ;
        RECT 30.120 241.050 50.725 241.920 ;
        RECT 51.720 241.050 66.085 242.070 ;
        RECT 67.080 241.050 81.445 242.070 ;
        RECT 82.440 241.050 96.805 242.070 ;
        RECT 97.800 241.920 142.405 242.070 ;
        RECT 97.800 241.050 113.935 241.920 ;
        RECT 121.800 241.050 142.405 241.920 ;
        RECT 143.400 241.050 157.765 242.070 ;
        RECT 158.760 241.050 173.125 242.070 ;
        RECT 174.120 241.050 188.485 242.070 ;
        RECT 0.000 229.170 189.120 241.050 ;
        RECT 0.000 228.150 37.560 229.170 ;
        RECT 38.280 228.150 129.240 229.170 ;
        RECT 129.960 228.960 189.120 229.170 ;
        RECT 129.960 228.360 189.270 228.960 ;
        RECT 129.960 228.150 189.120 228.360 ;
        RECT 0.000 228.070 189.120 228.150 ;
        RECT 0.000 227.050 37.560 228.070 ;
        RECT 38.280 227.050 129.240 228.070 ;
        RECT 129.960 227.860 189.120 228.070 ;
        RECT 129.960 227.260 189.270 227.860 ;
        RECT 129.960 227.050 189.120 227.260 ;
        RECT 0.000 226.760 189.120 227.050 ;
        RECT 0.000 226.160 189.270 226.760 ;
        RECT 0.000 219.950 189.120 226.160 ;
        RECT 0.000 219.330 36.090 219.950 ;
        RECT 36.710 219.330 189.120 219.950 ;
        RECT 0.000 218.850 189.120 219.330 ;
        RECT 0.000 218.230 36.090 218.850 ;
        RECT 36.710 218.230 189.120 218.850 ;
        RECT 0.000 205.950 189.120 218.230 ;
        RECT 0.000 205.940 68.730 205.950 ;
        RECT -0.150 205.340 68.730 205.940 ;
        RECT 0.000 205.330 68.730 205.340 ;
        RECT 69.350 205.330 172.410 205.950 ;
        RECT 173.030 205.330 189.120 205.950 ;
        RECT 0.000 204.850 189.120 205.330 ;
        RECT 0.000 204.840 68.730 204.850 ;
        RECT -0.150 204.240 68.730 204.840 ;
        RECT 0.000 204.230 68.730 204.240 ;
        RECT 69.350 204.230 172.410 204.850 ;
        RECT 173.030 204.230 189.120 204.850 ;
        RECT 0.000 198.450 189.120 204.230 ;
        RECT 0.000 198.240 37.960 198.450 ;
        RECT -0.150 197.640 37.960 198.240 ;
        RECT 0.000 197.430 37.960 197.640 ;
        RECT 38.680 198.250 189.120 198.450 ;
        RECT 38.680 197.630 68.730 198.250 ;
        RECT 69.350 197.630 172.410 198.250 ;
        RECT 173.030 197.630 189.120 198.250 ;
        RECT 38.680 197.430 189.120 197.630 ;
        RECT 0.000 197.350 189.120 197.430 ;
        RECT 0.000 197.140 37.960 197.350 ;
        RECT -0.150 196.540 37.960 197.140 ;
        RECT 0.000 196.330 37.960 196.540 ;
        RECT 38.680 197.150 189.120 197.350 ;
        RECT 38.680 196.530 68.730 197.150 ;
        RECT 69.350 196.530 172.410 197.150 ;
        RECT 173.030 196.530 189.120 197.150 ;
        RECT 38.680 196.330 189.120 196.530 ;
        RECT 0.000 184.250 189.120 196.330 ;
        RECT 0.000 183.630 36.090 184.250 ;
        RECT 36.710 183.630 189.120 184.250 ;
        RECT 0.000 183.150 189.120 183.630 ;
        RECT 0.000 182.530 36.090 183.150 ;
        RECT 36.710 182.530 189.120 183.150 ;
        RECT 0.000 175.430 189.120 182.530 ;
        RECT 0.000 174.410 19.320 175.430 ;
        RECT 20.040 174.410 189.120 175.430 ;
        RECT 0.000 174.330 189.120 174.410 ;
        RECT 0.000 173.310 19.320 174.330 ;
        RECT 20.040 173.310 189.120 174.330 ;
        RECT 0.000 161.230 189.120 173.310 ;
        RECT 0.000 160.610 31.850 161.230 ;
        RECT 32.470 160.610 54.890 161.230 ;
        RECT 55.510 160.610 79.850 161.230 ;
        RECT 80.470 160.610 104.810 161.230 ;
        RECT 105.430 160.610 189.120 161.230 ;
        RECT 0.000 160.130 189.120 160.610 ;
        RECT 0.000 159.510 31.850 160.130 ;
        RECT 32.470 159.510 54.890 160.130 ;
        RECT 55.510 159.510 79.850 160.130 ;
        RECT 80.470 159.510 104.810 160.130 ;
        RECT 105.430 159.510 189.120 160.130 ;
        RECT 0.000 153.580 189.120 159.510 ;
        RECT 0.000 153.530 152.680 153.580 ;
        RECT 0.000 152.910 31.850 153.530 ;
        RECT 32.470 152.910 54.890 153.530 ;
        RECT 55.510 152.910 122.010 153.530 ;
        RECT 122.630 152.910 137.370 153.530 ;
        RECT 137.990 152.910 152.680 153.530 ;
        RECT 0.000 152.860 152.680 152.910 ;
        RECT 153.400 153.530 189.120 153.580 ;
        RECT 153.400 152.910 168.090 153.530 ;
        RECT 168.710 152.910 189.120 153.530 ;
        RECT 153.400 152.860 189.120 152.910 ;
        RECT 0.000 152.480 189.120 152.860 ;
        RECT 0.000 152.430 152.680 152.480 ;
        RECT 0.000 151.810 31.850 152.430 ;
        RECT 32.470 151.810 54.890 152.430 ;
        RECT 55.510 151.810 122.010 152.430 ;
        RECT 122.630 151.810 137.370 152.430 ;
        RECT 137.990 151.810 152.680 152.430 ;
        RECT 0.000 151.760 152.680 151.810 ;
        RECT 153.400 152.430 189.120 152.480 ;
        RECT 153.400 151.810 168.090 152.430 ;
        RECT 168.710 151.810 189.120 152.430 ;
        RECT 153.400 151.760 189.120 151.810 ;
        RECT 0.000 139.730 189.120 151.760 ;
        RECT 0.000 138.710 19.320 139.730 ;
        RECT 20.040 138.710 106.600 139.730 ;
        RECT 107.320 138.710 189.120 139.730 ;
        RECT 0.000 138.630 189.120 138.710 ;
        RECT 0.000 137.610 19.320 138.630 ;
        RECT 20.040 137.610 106.600 138.630 ;
        RECT 107.320 137.610 189.120 138.630 ;
        RECT 0.000 130.510 189.120 137.610 ;
        RECT 0.000 129.890 36.090 130.510 ;
        RECT 36.710 129.890 189.120 130.510 ;
        RECT 0.000 129.410 189.120 129.890 ;
        RECT 0.000 128.790 36.090 129.410 ;
        RECT 36.710 128.790 189.120 129.410 ;
        RECT 0.000 116.510 189.120 128.790 ;
        RECT 0.000 116.500 68.730 116.510 ;
        RECT -0.150 115.900 68.730 116.500 ;
        RECT 0.000 115.890 68.730 115.900 ;
        RECT 69.350 115.890 172.410 116.510 ;
        RECT 173.030 115.890 189.120 116.510 ;
        RECT 0.000 115.410 189.120 115.890 ;
        RECT 0.000 115.400 68.730 115.410 ;
        RECT -0.150 114.800 68.730 115.400 ;
        RECT 0.000 114.790 68.730 114.800 ;
        RECT 69.350 114.790 172.410 115.410 ;
        RECT 173.030 114.790 189.120 115.410 ;
        RECT 0.000 109.010 189.120 114.790 ;
        RECT 0.000 108.800 37.960 109.010 ;
        RECT -0.150 108.200 37.960 108.800 ;
        RECT 0.000 107.990 37.960 108.200 ;
        RECT 38.680 108.810 189.120 109.010 ;
        RECT 38.680 108.190 68.730 108.810 ;
        RECT 69.350 108.190 172.410 108.810 ;
        RECT 173.030 108.190 189.120 108.810 ;
        RECT 38.680 107.990 189.120 108.190 ;
        RECT 0.000 107.910 189.120 107.990 ;
        RECT 0.000 107.700 37.960 107.910 ;
        RECT -0.150 107.100 37.960 107.700 ;
        RECT 0.000 106.890 37.960 107.100 ;
        RECT 38.680 107.710 189.120 107.910 ;
        RECT 38.680 107.090 68.730 107.710 ;
        RECT 69.350 107.090 172.410 107.710 ;
        RECT 173.030 107.090 189.120 107.710 ;
        RECT 38.680 106.890 189.120 107.090 ;
        RECT 0.000 94.810 189.120 106.890 ;
        RECT 0.000 94.190 36.090 94.810 ;
        RECT 36.710 94.190 189.120 94.810 ;
        RECT 0.000 93.710 189.120 94.190 ;
        RECT 0.000 93.090 36.090 93.710 ;
        RECT 36.710 93.090 189.120 93.710 ;
        RECT 0.000 86.880 189.120 93.090 ;
        RECT 0.000 86.280 189.270 86.880 ;
        RECT 0.000 85.990 189.120 86.280 ;
        RECT 0.000 84.970 37.560 85.990 ;
        RECT 38.280 84.970 129.240 85.990 ;
        RECT 129.960 85.780 189.120 85.990 ;
        RECT 129.960 85.180 189.270 85.780 ;
        RECT 129.960 84.970 189.120 85.180 ;
        RECT 0.000 84.890 189.120 84.970 ;
        RECT 0.000 83.870 37.560 84.890 ;
        RECT 38.280 83.870 129.240 84.890 ;
        RECT 129.960 84.680 189.120 84.890 ;
        RECT 129.960 84.080 189.270 84.680 ;
        RECT 129.960 83.870 189.120 84.080 ;
        RECT 0.000 71.990 189.120 83.870 ;
        RECT 0.000 71.120 22.255 71.990 ;
        RECT 30.120 71.120 50.725 71.990 ;
        RECT 0.000 70.970 50.725 71.120 ;
        RECT 51.720 70.970 66.085 71.990 ;
        RECT 67.080 70.970 81.445 71.990 ;
        RECT 82.440 70.970 96.805 71.990 ;
        RECT 97.800 71.120 113.935 71.990 ;
        RECT 121.800 71.120 142.405 71.990 ;
        RECT 97.800 70.970 142.405 71.120 ;
        RECT 143.400 70.970 157.765 71.990 ;
        RECT 158.760 70.970 173.125 71.990 ;
        RECT 174.120 70.970 188.485 71.990 ;
        RECT 0.000 70.890 189.120 70.970 ;
        RECT 0.000 69.870 27.755 70.890 ;
        RECT 30.120 69.870 47.555 70.890 ;
        RECT 51.720 69.870 62.915 70.890 ;
        RECT 67.080 69.870 78.275 70.890 ;
        RECT 82.440 69.870 93.635 70.890 ;
        RECT 97.800 69.870 119.435 70.890 ;
        RECT 121.800 69.870 139.235 70.890 ;
        RECT 143.400 69.870 154.595 70.890 ;
        RECT 158.760 69.870 169.955 70.890 ;
        RECT 174.120 69.870 185.315 70.890 ;
        RECT 0.000 64.290 189.120 69.870 ;
        RECT 0.000 63.270 27.755 64.290 ;
        RECT 30.120 63.270 47.555 64.290 ;
        RECT 51.720 63.270 62.915 64.290 ;
        RECT 67.080 63.270 78.275 64.290 ;
        RECT 82.440 63.270 93.635 64.290 ;
        RECT 97.800 63.270 119.435 64.290 ;
        RECT 121.800 63.270 139.235 64.290 ;
        RECT 143.400 63.270 154.595 64.290 ;
        RECT 158.760 63.270 169.955 64.290 ;
        RECT 174.120 63.270 185.315 64.290 ;
        RECT 0.000 63.190 189.120 63.270 ;
        RECT 0.000 63.040 50.725 63.190 ;
        RECT 0.000 62.170 22.255 63.040 ;
        RECT 30.120 62.170 50.725 63.040 ;
        RECT 51.720 62.170 66.085 63.190 ;
        RECT 67.080 62.170 81.445 63.190 ;
        RECT 82.440 62.170 96.805 63.190 ;
        RECT 97.800 63.040 142.405 63.190 ;
        RECT 97.800 62.170 113.935 63.040 ;
        RECT 121.800 62.170 142.405 63.040 ;
        RECT 143.400 62.170 157.765 63.190 ;
        RECT 158.760 62.170 173.125 63.190 ;
        RECT 174.120 62.170 188.485 63.190 ;
        RECT 0.000 50.290 189.120 62.170 ;
        RECT 0.000 49.270 37.560 50.290 ;
        RECT 38.280 49.270 129.240 50.290 ;
        RECT 129.960 50.080 189.120 50.290 ;
        RECT 129.960 49.480 189.270 50.080 ;
        RECT 129.960 49.270 189.120 49.480 ;
        RECT 0.000 49.190 189.120 49.270 ;
        RECT 0.000 48.170 37.560 49.190 ;
        RECT 38.280 48.170 129.240 49.190 ;
        RECT 129.960 48.980 189.120 49.190 ;
        RECT 129.960 48.380 189.270 48.980 ;
        RECT 129.960 48.170 189.120 48.380 ;
        RECT 0.000 47.880 189.120 48.170 ;
        RECT 0.000 47.280 189.270 47.880 ;
        RECT 0.000 41.070 189.120 47.280 ;
        RECT 0.000 40.450 36.090 41.070 ;
        RECT 36.710 40.450 189.120 41.070 ;
        RECT 0.000 39.970 189.120 40.450 ;
        RECT 0.000 39.350 36.090 39.970 ;
        RECT 36.710 39.350 189.120 39.970 ;
        RECT 0.000 27.070 189.120 39.350 ;
        RECT 0.000 27.060 68.730 27.070 ;
        RECT -0.150 26.460 68.730 27.060 ;
        RECT 0.000 26.450 68.730 26.460 ;
        RECT 69.350 26.450 172.410 27.070 ;
        RECT 173.030 26.450 189.120 27.070 ;
        RECT 0.000 25.970 189.120 26.450 ;
        RECT 0.000 25.960 68.730 25.970 ;
        RECT -0.150 25.360 68.730 25.960 ;
        RECT 0.000 25.350 68.730 25.360 ;
        RECT 69.350 25.350 172.410 25.970 ;
        RECT 173.030 25.350 189.120 25.970 ;
        RECT 0.000 19.570 189.120 25.350 ;
        RECT 0.360 18.550 37.960 19.570 ;
        RECT 38.680 19.370 189.120 19.570 ;
        RECT 38.680 18.750 68.730 19.370 ;
        RECT 69.350 18.750 172.410 19.370 ;
        RECT 173.030 18.750 189.120 19.370 ;
        RECT 38.680 18.550 189.120 18.750 ;
        RECT 0.000 18.470 189.120 18.550 ;
        RECT 0.360 17.450 37.960 18.470 ;
        RECT 38.680 18.270 189.120 18.470 ;
        RECT 38.680 17.650 68.730 18.270 ;
        RECT 69.350 17.650 172.410 18.270 ;
        RECT 173.030 17.650 189.120 18.270 ;
        RECT 38.680 17.450 189.120 17.650 ;
        RECT 0.000 5.370 189.120 17.450 ;
        RECT 0.000 4.750 36.090 5.370 ;
        RECT 36.710 4.750 189.120 5.370 ;
        RECT 0.000 4.270 189.120 4.750 ;
        RECT 0.000 4.090 36.090 4.270 ;
        RECT 0.000 3.370 23.160 4.090 ;
        RECT 23.880 3.650 36.090 4.090 ;
        RECT 36.710 3.650 189.120 4.270 ;
        RECT 23.880 3.370 189.120 3.650 ;
        RECT 0.000 0.000 189.120 3.370 ;
        RECT 51.970 -0.150 52.570 0.000 ;
        RECT 52.870 -0.150 53.470 0.000 ;
        RECT 53.890 -0.150 54.490 0.000 ;
        RECT 54.790 -0.150 55.390 0.000 ;
        RECT 69.250 -0.150 69.850 0.000 ;
        RECT 70.150 -0.150 70.750 0.000 ;
        RECT 71.170 -0.150 71.770 0.000 ;
        RECT 72.070 -0.150 72.670 0.000 ;
        RECT 86.530 -0.150 87.130 0.000 ;
        RECT 87.430 -0.150 88.030 0.000 ;
        RECT 88.450 -0.150 89.050 0.000 ;
        RECT 89.350 -0.150 89.950 0.000 ;
        RECT 103.810 -0.150 104.410 0.000 ;
        RECT 104.710 -0.150 105.310 0.000 ;
        RECT 105.730 -0.150 106.330 0.000 ;
        RECT 106.630 -0.150 107.230 0.000 ;
        RECT 121.090 -0.150 121.690 0.000 ;
        RECT 121.990 -0.150 122.590 0.000 ;
        RECT 123.010 -0.150 123.610 0.000 ;
        RECT 123.910 -0.150 124.510 0.000 ;
        RECT 138.370 -0.150 138.970 0.000 ;
        RECT 139.270 -0.150 139.870 0.000 ;
        RECT 140.290 -0.150 140.890 0.000 ;
        RECT 141.190 -0.150 141.790 0.000 ;
        RECT 155.650 -0.150 156.250 0.000 ;
        RECT 156.550 -0.150 157.150 0.000 ;
        RECT 157.570 -0.150 158.170 0.000 ;
        RECT 158.470 -0.150 159.070 0.000 ;
        RECT 172.930 -0.150 173.530 0.000 ;
        RECT 173.830 -0.150 174.430 0.000 ;
        RECT 174.850 -0.150 175.450 0.000 ;
        RECT 175.750 -0.150 176.350 0.000 ;
      RECT 105.020 159.720 105.220 159.920 ;
      RECT 105.020 160.820 105.220 161.020 ;
      RECT 119.645 242.360 121.590 242.960 ;
      RECT 114.145 241.260 121.590 241.710 ;
      RECT 129.450 228.360 129.750 228.960 ;
      RECT 129.450 227.260 129.750 227.860 ;
      RECT 172.620 197.840 172.820 198.040 ;
      RECT 172.620 196.740 172.820 196.940 ;
      RECT 172.620 204.440 172.820 204.640 ;
      RECT 172.620 205.540 172.820 205.740 ;
      RECT 119.645 248.960 121.590 249.560 ;
      RECT 114.145 250.210 121.590 250.660 ;
      RECT 129.450 262.960 129.750 263.560 ;
      RECT 129.450 264.060 129.750 264.660 ;
      RECT 172.620 287.280 172.820 287.480 ;
      RECT 172.620 286.180 172.820 286.380 ;
      RECT 172.620 293.880 172.820 294.080 ;
      RECT 172.620 294.980 172.820 295.180 ;
      RECT 32.060 159.720 32.260 159.920 ;
      RECT 32.060 160.820 32.260 161.020 ;
      RECT 80.060 159.720 80.260 159.920 ;
      RECT 80.060 160.820 80.260 161.020 ;
      RECT 55.100 159.720 55.300 159.920 ;
      RECT 55.100 160.820 55.300 161.020 ;
      RECT 36.300 183.840 36.500 184.040 ;
      RECT 36.300 182.740 36.500 182.940 ;
      RECT 36.300 218.440 36.500 218.640 ;
      RECT 36.300 219.540 36.500 219.740 ;
      RECT 27.965 242.360 29.910 242.960 ;
      RECT 22.465 241.260 29.910 241.710 ;
      RECT 37.770 228.360 38.070 228.960 ;
      RECT 37.770 227.260 38.070 227.860 ;
      RECT 68.940 197.840 69.140 198.040 ;
      RECT 68.940 196.740 69.140 196.940 ;
      RECT 68.940 204.440 69.140 204.640 ;
      RECT 68.940 205.540 69.140 205.740 ;
      RECT 36.300 273.280 36.500 273.480 ;
      RECT 36.300 272.180 36.500 272.380 ;
      RECT 36.300 307.880 36.500 308.080 ;
      RECT 36.300 308.980 36.500 309.180 ;
      RECT 27.965 248.960 29.910 249.560 ;
      RECT 22.465 250.210 29.910 250.660 ;
      RECT 37.770 262.960 38.070 263.560 ;
      RECT 37.770 264.060 38.070 264.660 ;
      RECT 68.940 287.280 69.140 287.480 ;
      RECT 68.940 286.180 69.140 286.380 ;
      RECT 68.940 293.880 69.140 294.080 ;
      RECT 68.940 294.980 69.140 295.180 ;
      RECT 19.530 173.520 19.830 174.120 ;
      RECT 19.530 174.620 19.830 175.220 ;
      RECT 36.300 130.100 36.500 130.300 ;
      RECT 27.965 70.080 29.910 70.680 ;
      RECT 22.465 71.330 29.910 71.780 ;
      RECT 37.770 84.080 38.070 84.680 ;
      RECT 37.770 85.180 38.070 85.780 ;
      RECT 68.940 108.400 69.140 108.600 ;
      RECT 68.940 107.300 69.140 107.500 ;
      RECT 68.940 115.000 69.140 115.200 ;
      RECT 68.940 116.100 69.140 116.300 ;
      RECT 19.530 138.920 19.830 139.520 ;
      RECT 19.530 137.820 19.830 138.420 ;
      RECT 32.060 153.120 32.260 153.320 ;
      RECT 32.060 152.020 32.260 152.220 ;
      RECT 55.100 153.120 55.300 153.320 ;
      RECT 55.100 152.020 55.300 152.220 ;
      RECT 36.300 4.960 36.500 5.160 ;
      RECT 36.300 3.860 36.500 4.060 ;
      RECT 36.300 39.560 36.500 39.760 ;
      RECT 36.300 40.660 36.500 40.860 ;
      RECT 27.965 63.480 29.910 64.080 ;
      RECT 22.465 62.380 29.910 62.830 ;
      RECT 37.770 49.480 38.070 50.080 ;
      RECT 37.770 48.380 38.070 48.980 ;
      RECT 68.940 18.960 69.140 19.160 ;
      RECT 68.940 17.860 69.140 18.060 ;
      RECT 68.940 25.560 69.140 25.760 ;
      RECT 68.940 26.660 69.140 26.860 ;
      RECT 36.300 94.400 36.500 94.600 ;
      RECT 36.300 93.300 36.500 93.500 ;
      RECT 36.300 129.000 36.500 129.200 ;
      RECT 172.620 108.400 172.820 108.600 ;
      RECT 172.620 107.300 172.820 107.500 ;
      RECT 172.620 115.000 172.820 115.200 ;
      RECT 172.620 116.100 172.820 116.300 ;
      RECT 119.645 63.480 121.590 64.080 ;
      RECT 114.145 62.380 121.590 62.830 ;
      RECT 106.810 138.920 107.110 139.520 ;
      RECT 106.810 137.820 107.110 138.420 ;
      RECT 129.450 49.480 129.750 50.080 ;
      RECT 129.450 48.380 129.750 48.980 ;
      RECT 122.220 153.120 122.420 153.320 ;
      RECT 122.220 152.020 122.420 152.220 ;
      RECT 172.620 18.960 172.820 19.160 ;
      RECT 172.620 17.860 172.820 18.060 ;
      RECT 137.580 153.120 137.780 153.320 ;
      RECT 137.580 152.020 137.780 152.220 ;
      RECT 172.620 25.560 172.820 25.760 ;
      RECT 172.620 26.660 172.820 26.860 ;
      RECT 168.300 153.120 168.500 153.320 ;
      RECT 168.300 152.020 168.500 152.220 ;
      RECT 119.645 70.080 121.590 70.680 ;
      RECT 114.145 71.330 121.590 71.780 ;
      RECT 129.450 84.080 129.750 84.680 ;
      RECT 129.450 85.180 129.750 85.780 ;
      LAYER Metal4 ;
        RECT 3.195 3.585 188.965 309.455 ;
      RECT 105.020 159.720 105.220 159.920 ;
      RECT 105.020 160.820 105.220 161.020 ;
      RECT 172.620 197.840 172.820 198.040 ;
      RECT 172.620 196.740 172.820 196.940 ;
      RECT 172.620 204.440 172.820 204.640 ;
      RECT 172.620 205.540 172.820 205.740 ;
      RECT 172.620 287.280 172.820 287.480 ;
      RECT 172.620 286.180 172.820 286.380 ;
      RECT 172.620 293.880 172.820 294.080 ;
      RECT 172.620 294.980 172.820 295.180 ;
      RECT 32.060 159.720 32.260 159.920 ;
      RECT 32.060 160.820 32.260 161.020 ;
      RECT 80.060 159.720 80.260 159.920 ;
      RECT 80.060 160.820 80.260 161.020 ;
      RECT 55.100 159.720 55.300 159.920 ;
      RECT 55.100 160.820 55.300 161.020 ;
      RECT 36.300 183.840 36.500 184.040 ;
      RECT 36.300 182.740 36.500 182.940 ;
      RECT 36.300 218.440 36.500 218.640 ;
      RECT 36.300 219.540 36.500 219.740 ;
      RECT 68.940 197.840 69.140 198.040 ;
      RECT 68.940 196.740 69.140 196.940 ;
      RECT 68.940 204.440 69.140 204.640 ;
      RECT 68.940 205.540 69.140 205.740 ;
      RECT 36.300 273.280 36.500 273.480 ;
      RECT 36.300 272.180 36.500 272.380 ;
      RECT 36.300 307.880 36.500 308.080 ;
      RECT 36.300 308.980 36.500 309.180 ;
      RECT 68.940 287.280 69.140 287.480 ;
      RECT 68.940 286.180 69.140 286.380 ;
      RECT 68.940 293.880 69.140 294.080 ;
      RECT 68.940 294.980 69.140 295.180 ;
      RECT 36.300 130.100 36.500 130.300 ;
      RECT 68.940 108.400 69.140 108.600 ;
      RECT 68.940 107.300 69.140 107.500 ;
      RECT 68.940 115.000 69.140 115.200 ;
      RECT 68.940 116.100 69.140 116.300 ;
      RECT 32.060 153.120 32.260 153.320 ;
      RECT 32.060 152.020 32.260 152.220 ;
      RECT 55.100 153.120 55.300 153.320 ;
      RECT 55.100 152.020 55.300 152.220 ;
      RECT 36.300 4.960 36.500 5.160 ;
      RECT 36.300 3.860 36.500 4.060 ;
      RECT 36.300 39.560 36.500 39.760 ;
      RECT 36.300 40.660 36.500 40.860 ;
      RECT 68.940 18.960 69.140 19.160 ;
      RECT 68.940 17.860 69.140 18.060 ;
      RECT 68.940 25.560 69.140 25.760 ;
      RECT 68.940 26.660 69.140 26.860 ;
      RECT 36.300 94.400 36.500 94.600 ;
      RECT 36.300 93.300 36.500 93.500 ;
      RECT 36.300 129.000 36.500 129.200 ;
      RECT 172.620 108.400 172.820 108.600 ;
      RECT 172.620 107.300 172.820 107.500 ;
      RECT 172.620 115.000 172.820 115.200 ;
      RECT 172.620 116.100 172.820 116.300 ;
      RECT 122.220 153.120 122.420 153.320 ;
      RECT 122.220 152.020 122.420 152.220 ;
      RECT 172.620 18.960 172.820 19.160 ;
      RECT 172.620 17.860 172.820 18.060 ;
      RECT 137.580 153.120 137.780 153.320 ;
      RECT 137.580 152.020 137.780 152.220 ;
      RECT 172.620 25.560 172.820 25.760 ;
      RECT 172.620 26.660 172.820 26.860 ;
      RECT 168.300 153.120 168.500 153.320 ;
      RECT 168.300 152.020 168.500 152.220 ;
      LAYER Metal5 ;
        RECT 3.195 3.815 188.965 309.225 ;
  END
END sr16_rx4
END LIBRARY

